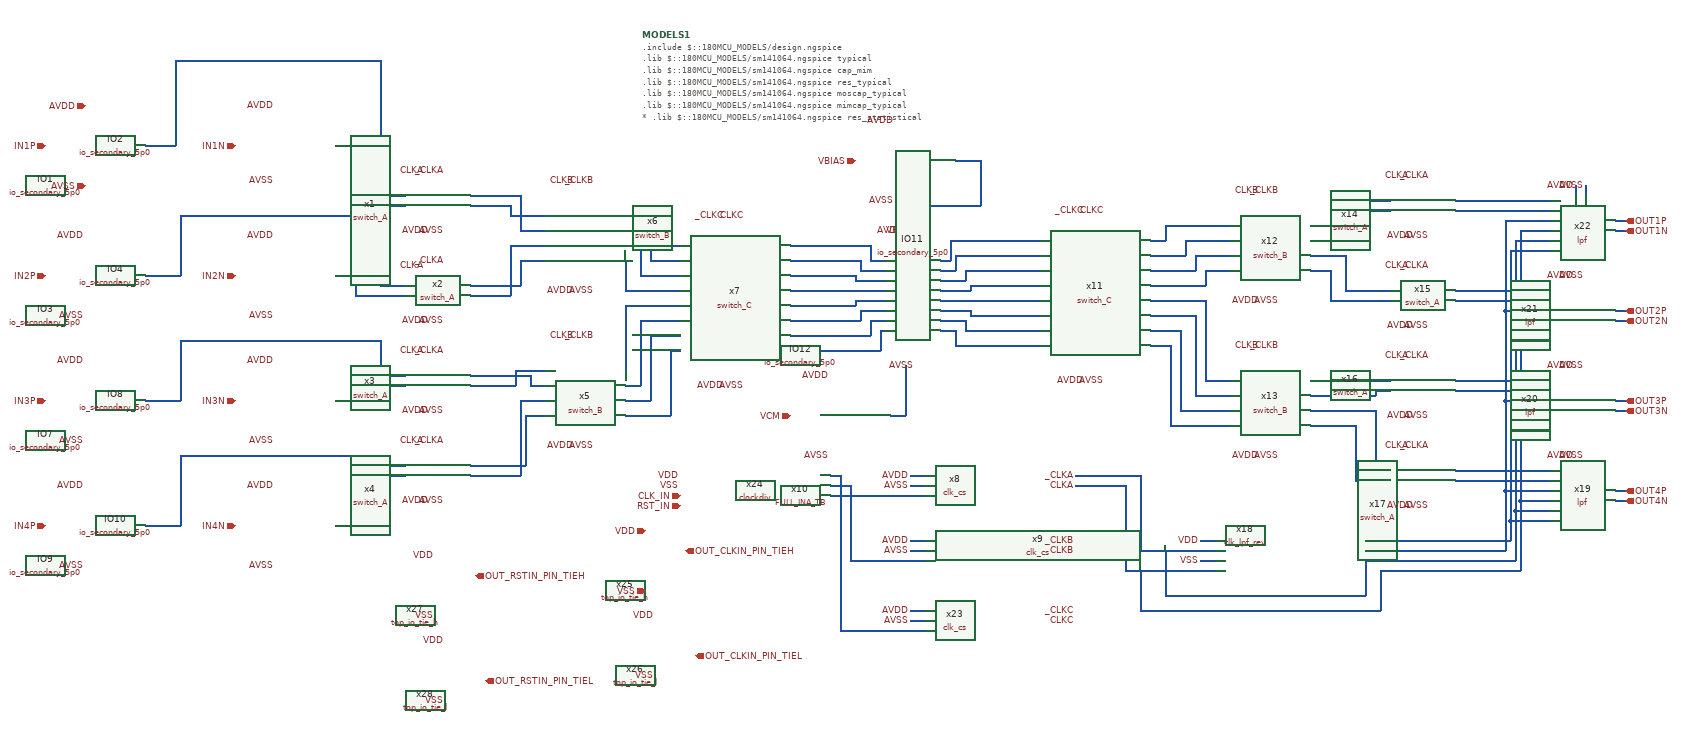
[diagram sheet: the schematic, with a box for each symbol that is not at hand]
v {xschem version=3.4.7 file_version=1.2}
G {}
K {}
V {}
S {}
E {}
N 1560 -610 1590 -610 {lab=AVDD}
N 1560 -590 1590 -590 {lab=AVSS}
N 1560 -570 1590 -570 {lab=#net1}
N 1560 -440 1590 -440 {lab=#net2}
N 1560 -460 1590 -460 {lab=AVSS}
N 1560 -480 1590 -480 {lab=AVDD}
N 1560 -340 1590 -340 {lab=AVDD}
N 1580 -320 1590 -320 {lab=AVSS}
N 1560 -300 1590 -300 {lab=#net3}
N 680 -1170 780 -1170 {lab=#net4}
N 780 -1170 780 -1100 {lab=#net4}
N 780 -1100 830 -1100 {lab=#net4}
N 760 -1130 830 -1130 {lab=#net5}
N 760 -1150 760 -1130 {lab=#net5}
N 680 -1150 760 -1150 {lab=#net5}
N 680 -990 780 -990 {lab=#net6}
N 780 -1040 780 -990 {lab=#net6}
N 780 -1040 830 -1040 {lab=#net6}
N 760 -1070 830 -1070 {lab=#net7}
N 760 -1070 760 -970 {lab=#net7}
N 680 -970 760 -970 {lab=#net7}
N 680 -810 800 -810 {lab=#net8}
N 800 -810 800 -790 {lab=#net8}
N 800 -790 830 -790 {lab=#net8}
N 680 -790 770 -790 {lab=#net9}
N 770 -820 770 -790 {lab=#net9}
N 770 -820 830 -820 {lab=#net9}
N 680 -630 790 -630 {lab=#net10}
N 790 -730 790 -630 {lab=#net10}
N 790 -730 830 -730 {lab=#net10}
N 780 -760 830 -760 {lab=#net11}
N 780 -760 780 -610 {lab=#net11}
N 680 -610 780 -610 {lab=#net11}
N 990 -1130 1060 -1130 {lab=#net12}
N 1060 -1130 1060 -1070 {lab=#net12}
N 1060 -1070 1100 -1070 {lab=#net12}
N 990 -1100 1040 -1100 {lab=#net13}
N 1040 -1100 1040 -1040 {lab=#net13}
N 1040 -1040 1100 -1040 {lab=#net13}
N 990 -1070 1020 -1070 {lab=#net14}
N 1020 -1070 1020 -1010 {lab=#net14}
N 1020 -1010 1100 -1010 {lab=#net14}
N 990 -1040 990 -980 {lab=#net15}
N 990 -980 1100 -980 {lab=#net15}
N 500 -1170 550 -1170 {lab=#net16}
N 500 -990 550 -990 {lab=#net17}
N 500 -810 550 -810 {lab=#net18}
N 500 -630 550 -630 {lab=#net19}
N 2040 -1080 2070 -1080 {lab=#net20}
N 2070 -1110 2070 -1080 {lab=#net20}
N 2070 -1110 2200 -1110 {lab=#net20}
N 2110 -1080 2200 -1080 {lab=#net21}
N 2110 -1080 2110 -1050 {lab=#net21}
N 2040 -1050 2110 -1050 {lab=#net21}
N 2040 -1020 2130 -1020 {lab=#net22}
N 2130 -1050 2130 -1020 {lab=#net22}
N 2130 -1050 2200 -1050 {lab=#net22}
N 2040 -990 2150 -990 {lab=#net23}
N 2150 -1020 2150 -990 {lab=#net23}
N 2150 -1020 2200 -1020 {lab=#net23}
N 2040 -960 2150 -960 {lab=#net24}
N 2150 -960 2150 -800 {lab=#net24}
N 2150 -800 2200 -800 {lab=#net24}
N 2040 -930 2130 -930 {lab=#net25}
N 2130 -930 2130 -770 {lab=#net25}
N 2130 -770 2200 -770 {lab=#net25}
N 2040 -900 2100 -900 {lab=#net26}
N 2100 -900 2100 -740 {lab=#net26}
N 2100 -740 2200 -740 {lab=#net26}
N 2040 -870 2080 -870 {lab=#net27}
N 2080 -870 2080 -710 {lab=#net27}
N 2080 -710 2200 -710 {lab=#net27}
N 2360 -1110 2400 -1110 {lab=#net28}
N 2400 -1160 2400 -1110 {lab=#net28}
N 2400 -1160 2520 -1160 {lab=#net28}
N 2360 -1080 2430 -1080 {lab=#net29}
N 2430 -1140 2430 -1080 {lab=#net29}
N 2430 -1140 2520 -1140 {lab=#net29}
N 2360 -1050 2430 -1050 {lab=#net30}
N 2430 -1050 2430 -980 {lab=#net30}
N 2430 -980 2520 -980 {lab=#net30}
N 2360 -1020 2400 -1020 {lab=#net31}
N 2400 -1020 2400 -960 {lab=#net31}
N 2400 -960 2520 -960 {lab=#net31}
N 2360 -800 2520 -800 {lab=#net32}
N 2360 -770 2490 -770 {lab=#net33}
N 2490 -780 2490 -770 {lab=#net33}
N 2490 -780 2520 -780 {lab=#net33}
N 2360 -740 2490 -740 {lab=#net34}
N 2490 -740 2490 -620 {lab=#net34}
N 2490 -620 2520 -620 {lab=#net34}
N 2360 -710 2450 -710 {lab=#net35}
N 2450 -710 2450 -610 {lab=#net35}
N 2450 -610 2450 -600 {lab=#net35}
N 2450 -600 2520 -600 {lab=#net35}
N 1320 -1070 1360 -1070 {lab=#net36}
N 1320 -1040 1380 -1040 {lab=#net37}
N 1320 -1010 1410 -1010 {lab=#net38}
N 1320 -980 1420 -980 {lab=#net39}
N 1320 -950 1420 -950 {lab=#net40}
N 1320 -920 1400 -920 {lab=#net41}
N 1320 -890 1370 -890 {lab=#net42}
N 1320 -860 1340 -860 {lab=#net43}
N 1790 -1080 1820 -1080 {lab=#net44}
N 1760 -1050 1820 -1050 {lab=#net45}
N 1740 -1020 1820 -1020 {lab=#net46}
N 1710 -990 1820 -990 {lab=#net47}
N 1740 -960 1820 -960 {lab=#net48}
N 1760 -930 1820 -930 {lab=#net49}
N 1780 -900 1820 -900 {lab=#net50}
N 1810 -870 1820 -870 {lab=#net51}
N 1360 -1070 1480 -1070 {lab=#net36}
N 1480 -1070 1480 -1040 {lab=#net36}
N 1480 -1040 1510 -1040 {lab=#net36}
N 1380 -1040 1460 -1040 {lab=#net37}
N 1460 -1040 1460 -1020 {lab=#net37}
N 1460 -1020 1510 -1020 {lab=#net37}
N 1410 -1010 1450 -1010 {lab=#net38}
N 1450 -1010 1450 -1000 {lab=#net38}
N 1450 -1000 1510 -1000 {lab=#net38}
N 1420 -980 1510 -980 {lab=#net39}
N 1420 -950 1450 -950 {lab=#net40}
N 1450 -960 1450 -950 {lab=#net40}
N 1450 -960 1510 -960 {lab=#net40}
N 1400 -920 1460 -920 {lab=#net41}
N 1460 -940 1460 -920 {lab=#net41}
N 1460 -940 1510 -940 {lab=#net41}
N 1370 -890 1480 -890 {lab=#net42}
N 1480 -920 1480 -890 {lab=#net42}
N 1480 -920 1510 -920 {lab=#net42}
N 1340 -860 1500 -860 {lab=#net43}
N 1500 -900 1500 -860 {lab=#net43}
N 1500 -900 1510 -900 {lab=#net43}
N 1620 -900 1650 -900 {lab=#net51}
N 1650 -900 1650 -870 {lab=#net51}
N 1650 -870 1810 -870 {lab=#net51}
N 1670 -900 1780 -900 {lab=#net50}
N 1670 -920 1670 -900 {lab=#net50}
N 1620 -920 1670 -920 {lab=#net50}
N 1680 -930 1760 -930 {lab=#net49}
N 1680 -940 1680 -930 {lab=#net49}
N 1620 -940 1680 -940 {lab=#net49}
N 1620 -960 1740 -960 {lab=#net48}
N 1680 -990 1710 -990 {lab=#net47}
N 1680 -990 1680 -980 {lab=#net47}
N 1620 -980 1680 -980 {lab=#net47}
N 1670 -1020 1740 -1020 {lab=#net46}
N 1670 -1020 1670 -1000 {lab=#net46}
N 1620 -1000 1670 -1000 {lab=#net46}
N 1650 -1050 1760 -1050 {lab=#net45}
N 1650 -1050 1650 -1020 {lab=#net45}
N 1620 -1020 1650 -1020 {lab=#net45}
N 1640 -1080 1790 -1080 {lab=#net44}
N 1640 -1080 1640 -1040 {lab=#net44}
N 1620 -1040 1640 -1040 {lab=#net44}
N 2650 -1140 2820 -1140 {lab=#net52}
N 2140 -480 2170 -480 {lab=VDD}
N 2470 -480 2760 -480 {lab=#net53}
N 2760 -520 2760 -480 {lab=#net53}
N 2760 -520 2820 -520 {lab=#net53}
N 2470 -460 2750 -460 {lab=#net54}
N 2750 -580 2750 -460 {lab=#net54}
N 2750 -580 2820 -580 {lab=#net54}
N 2470 -440 2770 -440 {lab=_CLKA}
N 2770 -540 2770 -440 {lab=_CLKA}
N 2770 -540 2820 -540 {lab=_CLKA}
N 2780 -560 2780 -420 {lab=CLKA}
N 2780 -560 2820 -560 {lab=CLKA}
N 2750 -760 2750 -580 {lab=#net54}
N 2750 -760 2820 -760 {lab=#net54}
N 2750 -940 2750 -760 {lab=#net54}
N 2750 -940 2820 -940 {lab=#net54}
N 2750 -1120 2750 -940 {lab=#net54}
N 2750 -1120 2820 -1120 {lab=#net54}
N 2780 -740 2780 -560 {lab=CLKA}
N 2780 -740 2820 -740 {lab=CLKA}
N 2780 -920 2780 -740 {lab=CLKA}
N 2780 -920 2820 -920 {lab=CLKA}
N 2780 -1100 2780 -920 {lab=CLKA}
N 2780 -1100 2820 -1100 {lab=CLKA}
N 2770 -720 2770 -540 {lab=_CLKA}
N 2770 -720 2820 -720 {lab=_CLKA}
N 2770 -900 2770 -720 {lab=_CLKA}
N 2770 -900 2820 -900 {lab=_CLKA}
N 2770 -1080 2770 -900 {lab=_CLKA}
N 2770 -1080 2820 -1080 {lab=_CLKA}
N 2760 -1060 2820 -1060 {lab=#net53}
N 2760 -1060 2760 -520 {lab=#net53}
N 2760 -700 2820 -700 {lab=#net53}
N 2760 -880 2820 -880 {lab=#net53}
N 2820 -1160 2840 -1160 {lab=#net55}
N 2820 -1140 2840 -1140 {lab=#net52}
N 2820 -1120 2840 -1120 {lab=#net54}
N 2820 -1100 2840 -1100 {lab=CLKA}
N 2820 -1080 2840 -1080 {lab=_CLKA}
N 2820 -1060 2840 -1060 {lab=#net53}
N 2820 -960 2840 -960 {lab=#net56}
N 2820 -940 2840 -940 {lab=#net54}
N 2820 -920 2840 -920 {lab=CLKA}
N 2820 -900 2840 -900 {lab=_CLKA}
N 2820 -880 2840 -880 {lab=#net53}
N 2820 -800 2840 -800 {lab=#net57}
N 2820 -780 2840 -780 {lab=#net58}
N 2820 -760 2840 -760 {lab=#net54}
N 2820 -740 2840 -740 {lab=CLKA}
N 2820 -720 2840 -720 {lab=_CLKA}
N 2820 -700 2840 -700 {lab=#net53}
N 2820 -620 2840 -620 {lab=#net59}
N 2820 -600 2840 -600 {lab=#net60}
N 2820 -580 2840 -580 {lab=#net54}
N 2820 -560 2840 -560 {lab=CLKA}
N 2820 -540 2840 -540 {lab=_CLKA}
N 2820 -520 2840 -520 {lab=#net53}
N 2970 -580 2990 -580 {lab=OUT4P}
N 2970 -560 2990 -560 {lab=OUT4N}
N 2970 -740 2990 -740 {lab=OUT3N}
N 2970 -760 2990 -760 {lab=OUT3P}
N 2970 -920 2990 -920 {lab=OUT2N}
N 2970 -940 2990 -940 {lab=OUT2P}
N 2890 -1190 2890 -1170 {lab=AVDD}
N 2910 -1190 2910 -1170 {lab=AVSS}
N 2970 -1120 2990 -1120 {lab=OUT1P}
N 2970 -1100 2990 -1100 {lab=OUT1N}
N 1560 -320 1580 -320 {lab=AVSS}
N 500 -1150 550 -1150 {lab=#net61}
N 500 -970 550 -970 {lab=#net62}
N 500 -790 550 -790 {lab=#net63}
N 500 -610 550 -610 {lab=#net64}
N 2650 -980 2840 -980 {lab=#net65}
N 2650 -960 2820 -960 {lab=#net56}
N 2650 -800 2820 -800 {lab=#net57}
N 2650 -780 2820 -780 {lab=#net58}
N 2650 -1160 2820 -1160 {lab=#net55}
N 2650 -620 2820 -620 {lab=#net59}
N 2650 -600 2820 -600 {lab=#net60}
N 990 -950 990 -820 {lab=#net66}
N 990 -950 1100 -950 {lab=#net66}
N 990 -790 1020 -790 {lab=#net67}
N 1020 -920 1020 -790 {lab=#net67}
N 1020 -920 1100 -920 {lab=#net67}
N 990 -760 1040 -760 {lab=#net68}
N 1040 -890 1040 -760 {lab=#net68}
N 1040 -890 1100 -890 {lab=#net68}
N 990 -730 1080 -730 {lab=#net69}
N 1080 -860 1080 -730 {lab=#net69}
N 1080 -860 1100 -860 {lab=#net69}
N 2020 -460 2170 -460 {lab=_CLKA}
N 2020 -610 2020 -460 {lab=_CLKA}
N 1890 -610 2020 -610 {lab=_CLKA}
N 1890 -590 1990 -590 {lab=CLKA}
N 1990 -590 1990 -420 {lab=CLKA}
N 1990 -420 2170 -420 {lab=CLKA}
N 2140 -440 2170 -440 {lab=VSS}
N 2500 -420 2780 -420 {lab=CLKA}
N 2070 -460 2070 -370 {lab=_CLKA}
N 2070 -370 2470 -370 {lab=_CLKA}
N 2470 -440 2470 -370 {lab=_CLKA}
N 2020 -420 2020 -340 {lab=CLKA}
N 2020 -340 2500 -340 {lab=CLKA}
N 2500 -420 2500 -340 {lab=CLKA}
N 30 -1270 90 -1270 {lab=#net16}
N 90 -1440 90 -1270 {lab=#net16}
N 90 -1440 500 -1440 {lab=#net16}
N 500 -1440 500 -1170 {lab=#net16}
N 410 -1270 460 -1270 {lab=#net61}
N 460 -1270 460 -1150 {lab=#net61}
N 460 -1150 500 -1150 {lab=#net61}
N 30 -1010 100 -1010 {lab=#net17}
N 100 -1130 100 -1010 {lab=#net17}
N 100 -1130 500 -1130 {lab=#net17}
N 500 -1130 500 -990 {lab=#net17}
N 410 -1010 450 -1010 {lab=#net62}
N 450 -1010 450 -970 {lab=#net62}
N 450 -970 500 -970 {lab=#net62}
N 30 -760 100 -760 {lab=#net18}
N 100 -880 100 -760 {lab=#net18}
N 100 -880 500 -880 {lab=#net18}
N 500 -880 500 -810 {lab=#net18}
N 410 -760 500 -760 {lab=#net63}
N 500 -790 500 -760 {lab=#net63}
N 30 -510 100 -510 {lab=#net19}
N 100 -650 100 -510 {lab=#net19}
N 100 -650 500 -650 {lab=#net19}
N 500 -650 500 -630 {lab=#net19}
N 410 -510 500 -510 {lab=#net64}
N 500 -610 500 -510 {lab=#net64}
N 1400 -610 1420 -610 {lab=#net3}
N 1420 -610 1420 -300 {lab=#net3}
N 1420 -300 1560 -300 {lab=#net3}
N 1400 -590 1440 -590 {lab=#net2}
N 1440 -590 1440 -440 {lab=#net2}
N 1440 -440 1560 -440 {lab=#net2}
N 1400 -570 1560 -570 {lab=#net1}
N 1550 -830 1550 -730 {lab=#net70}
N 1520 -730 1550 -730 {lab=#net70}
N 1650 -1240 1700 -1240 {lab=VBIAS}
N 1570 -1150 1570 -1100 {lab=VBIAS}
N 1570 -1150 1700 -1150 {lab=VBIAS}
N 1700 -1160 1700 -1150 {lab=VBIAS}
N 1700 -1240 1700 -1160 {lab=VBIAS}
C {devices/code_shown.sym} 1024.998521357774 -1491.620232462883 0 0 {name=MODELS1 only_toplevel=true
format="tcleval( @value )"
value="
.include $::180MCU_MODELS/design.ngspice
.lib $::180MCU_MODELS/sm141064.ngspice typical
.lib $::180MCU_MODELS/sm141064.ngspice cap_mim
.lib $::180MCU_MODELS/sm141064.ngspice res_typical
.lib $::180MCU_MODELS/sm141064.ngspice moscap_typical
.lib $::180MCU_MODELS/sm141064.ngspice mimcap_typical
* .lib $::180MCU_MODELS/sm141064.ngspice res_statistical
"}
C {xschem top/Chopper Switch/switch_A.sym} 510 -1100 0 0 {name=x1}
C {xschem top/Chopper Switch/switch_A.sym} 510 -920 0 0 {name=x2}
C {xschem top/Chopper Switch/switch_A.sym} 510 -740 0 0 {name=x3}
C {xschem top/Chopper Switch/switch_A.sym} 510 -560 0 0 {name=x4}
C {xschem top/Chopper Switch/switch_B.sym} 970 -670 0 0 {name=x5}
C {xschem top/Chopper Switch/switch_B.sym} 970 -980 0 0 {name=x6}
C {xschem top/Chopper Switch/switch_C.sym} 1210 -1010 0 0 {name=x7}
C {xschem top/Chopper Switch/switch_C.sym} 1930 -1020 0 0 {name=x11}
C {xschem top/Chopper Switch/switch_B.sym} 2340 -960 0 0 {name=x12}
C {xschem top/Chopper Switch/switch_B.sym} 2340 -650 0 0 {name=x13}
C {xschem top/Chopper Switch/switch_A.sym} 2480 -1090 0 0 {name=x14}
C {xschem top/Chopper Switch/switch_A.sym} 2480 -910 0 0 {name=x15}
C {xschem top/Chopper Switch/switch_A.sym} 2480 -730 0 0 {name=x16}
C {xschem top/LPF/lpf.sym} 2970 -930 0 0 {name=x21}
C {xschem top/LPF/lpf.sym} 2970 -1110 0 0 {name=x22}
C {xschem top/Chopper Switch/switch_A.sym} 2480 -550 0 0 {name=x17}
C {xschem top/INA/FULL_INA_TB.sym} 1320 -510 0 0 {name=x10}
C {lab_wire.sym} 1560 -590 0 0 {name=p86 lab=AVSS}
C {lab_wire.sym} 1560 -610 0 0 {name=p87 lab=AVDD}
C {xschem top/Chopper Switch/Complementary CLK for Switches/clk_cs.sym} 1740 -590 0 0 {name=x8}
C {xschem top/Chopper Switch/Complementary CLK for Switches/clk_cs.sym} 1740 -460 0 0 {name=x9}
C {xschem top/Chopper Switch/Complementary CLK for Switches/clk_cs.sym} 1740 -320 0 0 {name=x23}
C {lab_wire.sym} 1560 -480 0 0 {name=p2 lab=AVDD}
C {lab_wire.sym} 1560 -460 0 0 {name=p3 lab=AVSS}
C {lab_wire.sym} 1560 -340 0 0 {name=p13 lab=AVDD}
C {lab_wire.sym} 1560 -320 0 0 {name=p14 lab=AVSS}
C {lab_wire.sym} 1890 -610 0 0 {name=p88 lab=_CLKA}
C {lab_wire.sym} 1890 -590 0 0 {name=p89 lab=CLKA}
C {lab_wire.sym} 1890 -480 0 0 {name=p94 lab=_CLKB}
C {lab_wire.sym} 1890 -460 0 0 {name=p95 lab=CLKB}
C {lab_wire.sym} 1890 -340 0 0 {name=p96 lab=_CLKC}
C {lab_wire.sym} 1890 -320 0 0 {name=p97 lab=CLKC}
C {lab_wire.sym} 2140 -440 0 0 {name=p50 lab=VSS}
C {lab_wire.sym} 2140 -480 0 0 {name=p98 lab=VDD}
C {lab_wire.sym} 590 -1220 1 0 {name=p12 lab=CLKA}
C {lab_wire.sym} 630 -1220 1 0 {name=p15 lab=_CLKA}
C {lab_wire.sym} 590 -1030 1 0 {name=p16 lab=CLKA}
C {lab_wire.sym} 630 -1040 1 0 {name=p17 lab=_CLKA}
C {lab_wire.sym} 590 -860 1 0 {name=p18 lab=CLKA}
C {lab_wire.sym} 630 -860 1 0 {name=p19 lab=_CLKA}
C {lab_wire.sym} 590 -680 1 0 {name=p20 lab=CLKA}
C {lab_wire.sym} 630 -680 1 0 {name=p21 lab=_CLKA}
C {lab_wire.sym} 630 -560 3 0 {name=p22 lab=AVSS}
C {lab_wire.sym} 600 -560 3 0 {name=p32 lab=AVDD}
C {lab_wire.sym} 630 -740 3 0 {name=p33 lab=AVSS}
C {lab_wire.sym} 600 -740 3 0 {name=p34 lab=AVDD}
C {lab_wire.sym} 630 -920 3 0 {name=p35 lab=AVSS}
C {lab_wire.sym} 600 -920 3 0 {name=p100 lab=AVDD}
C {lab_wire.sym} 630 -1100 3 0 {name=p101 lab=AVSS}
C {lab_wire.sym} 600 -1100 3 0 {name=p102 lab=AVDD}
C {lab_wire.sym} 930 -670 3 0 {name=p23 lab=AVSS}
C {lab_wire.sym} 890 -670 3 0 {name=p24 lab=AVDD}
C {lab_wire.sym} 930 -980 3 0 {name=p25 lab=AVSS}
C {lab_wire.sym} 890 -980 3 0 {name=p26 lab=AVDD}
C {lab_wire.sym} 1230 -790 3 0 {name=p30 lab=AVSS}
C {lab_wire.sym} 1190 -790 3 0 {name=p31 lab=AVDD}
C {lab_wire.sym} 890 -1200 1 0 {name=p29 lab=CLKB}
C {lab_wire.sym} 930 -1200 1 0 {name=p107 lab=_CLKB}
C {lab_wire.sym} 890 -890 1 0 {name=p108 lab=CLKB}
C {lab_wire.sym} 930 -890 1 0 {name=p109 lab=_CLKB}
C {lab_wire.sym} 1190 -1130 1 0 {name=p27 lab=_CLKC}
C {lab_wire.sym} 1230 -1130 1 0 {name=p28 lab=CLKC}
C {lab_wire.sym} 1550 -1100 1 0 {name=p42 lab=AVDD}
C {lab_wire.sym} 1570 -1100 1 0 {name=p43 lab=VBIAS}
C {lab_wire.sym} 1570 -830 3 0 {name=p49 lab=AVSS}
C {opin.sym} 2990 -1120 0 0 {name=p51 lab=OUT1P}
C {opin.sym} 2990 -1100 0 0 {name=p58 lab=OUT1N}
C {opin.sym} 2990 -940 0 0 {name=p59 lab=OUT2P}
C {opin.sym} 2990 -920 0 0 {name=p60 lab=OUT2N}
C {opin.sym} 2990 -760 0 0 {name=p90 lab=OUT3P}
C {opin.sym} 2990 -740 0 0 {name=p91 lab=OUT3N}
C {opin.sym} 2990 -580 0 0 {name=p92 lab=OUT4P}
C {opin.sym} 2990 -560 0 0 {name=p93 lab=OUT4N}
C {lab_wire.sym} 1910 -1140 1 0 {name=p73 lab=_CLKC}
C {lab_wire.sym} 1950 -1140 1 0 {name=p74 lab=CLKC}
C {lab_wire.sym} 1950 -800 3 0 {name=p75 lab=AVSS}
C {lab_wire.sym} 1910 -800 3 0 {name=p139 lab=AVDD}
C {lab_wire.sym} 2260 -1180 1 0 {name=p61 lab=CLKB}
C {lab_wire.sym} 2300 -1180 1 0 {name=p62 lab=_CLKB}
C {lab_wire.sym} 2260 -870 1 0 {name=p63 lab=CLKB}
C {lab_wire.sym} 2300 -870 1 0 {name=p64 lab=_CLKB}
C {lab_wire.sym} 2300 -650 3 0 {name=p65 lab=AVSS}
C {lab_wire.sym} 2260 -650 3 0 {name=p66 lab=AVDD}
C {lab_wire.sym} 2300 -960 3 0 {name=p67 lab=AVSS}
C {lab_wire.sym} 2260 -960 3 0 {name=p68 lab=AVDD}
C {lab_wire.sym} 2560 -1210 1 0 {name=p69 lab=CLKA}
C {lab_wire.sym} 2600 -1210 1 0 {name=p70 lab=_CLKA}
C {lab_wire.sym} 2560 -1030 1 0 {name=p71 lab=CLKA}
C {lab_wire.sym} 2600 -1030 1 0 {name=p72 lab=_CLKA}
C {lab_wire.sym} 2560 -850 1 0 {name=p76 lab=CLKA}
C {lab_wire.sym} 2600 -850 1 0 {name=p77 lab=_CLKA}
C {lab_wire.sym} 2600 -550 3 0 {name=p78 lab=AVSS}
C {lab_wire.sym} 2570 -550 3 0 {name=p79 lab=AVDD}
C {lab_wire.sym} 2600 -730 3 0 {name=p80 lab=AVSS}
C {lab_wire.sym} 2570 -730 3 0 {name=p81 lab=AVDD}
C {lab_wire.sym} 2600 -910 3 0 {name=p140 lab=AVSS}
C {lab_wire.sym} 2570 -910 3 0 {name=p141 lab=AVDD}
C {lab_wire.sym} 2600 -1090 3 0 {name=p142 lab=AVSS}
C {lab_wire.sym} 2570 -1090 3 0 {name=p143 lab=AVDD}
C {xschem top/LPF/lpf.sym} 2970 -750 0 0 {name=x20}
C {xschem top/LPF/lpf.sym} 2970 -570 0 0 {name=x19}
C {lab_wire.sym} 2910 -1190 1 0 {name=p82 lab=AVSS}
C {lab_wire.sym} 2890 -1190 1 0 {name=p83 lab=AVDD}
C {lab_wire.sym} 2890 -1010 1 0 {name=p84 lab=AVDD}
C {lab_wire.sym} 2910 -1010 1 0 {name=p85 lab=AVSS}
C {lab_wire.sym} 2910 -830 1 0 {name=p144 lab=AVSS}
C {lab_wire.sym} 2910 -650 1 0 {name=p145 lab=AVSS}
C {lab_wire.sym} 2890 -830 1 0 {name=p146 lab=AVDD}
C {lab_wire.sym} 2890 -650 1 0 {name=p147 lab=AVDD}
C {xschem top/LPF/Complementary CLK for LPF/clk_lpf_rev.sym} 2320 -450 0 0 {name=x18}
C {gLayout/tutorial/io_secondary_5p0.sym} -170 -1190 0 0 {name=IO1
spiceprefix=X
}
C {gLayout/tutorial/io_secondary_5p0.sym} 210 -1190 0 0 {name=IO2
spiceprefix=X
}
C {gLayout/tutorial/io_secondary_5p0.sym} -170 -930 0 0 {name=IO3
spiceprefix=X
}
C {ipin.sym} -90 -1350 1 0 {name=p41 lab=AVDD}
C {ipin.sym} -90 -1190 3 0 {name=p44 lab=AVSS}
C {lab_wire.sym} 290 -1200 3 0 {name=p45 lab=AVSS}
C {lab_wire.sym} 290 -1350 1 0 {name=p46 lab=AVDD}
C {iopin.sym} -170 -1270 2 0 {name=p47 lab=IN1P}
C {iopin.sym} 210 -1270 2 0 {name=p48 lab=IN1N}
C {lab_wire.sym} -90 -1090 1 0 {name=p52 lab=AVDD}
C {lab_wire.sym} -90 -930 3 0 {name=p53 lab=AVSS}
C {iopin.sym} -170 -1010 2 0 {name=p54 lab=IN2P}
C {gLayout/tutorial/io_secondary_5p0.sym} 210 -930 0 0 {name=IO4
spiceprefix=X
}
C {lab_wire.sym} 290 -1090 1 0 {name=p55 lab=AVDD}
C {lab_wire.sym} 290 -930 3 0 {name=p56 lab=AVSS}
C {iopin.sym} 210 -1010 2 0 {name=p57 lab=IN2N}
C {gLayout/tutorial/io_secondary_5p0.sym} -170 -680 0 0 {name=IO7
spiceprefix=X
}
C {lab_wire.sym} -90 -840 1 0 {name=p115 lab=AVDD}
C {lab_wire.sym} -90 -680 3 0 {name=p116 lab=AVSS}
C {iopin.sym} -170 -760 2 0 {name=p117 lab=IN3P}
C {gLayout/tutorial/io_secondary_5p0.sym} 210 -680 0 0 {name=IO8
spiceprefix=X
}
C {lab_wire.sym} 290 -840 1 0 {name=p120 lab=AVDD}
C {lab_wire.sym} 290 -680 3 0 {name=p121 lab=AVSS}
C {iopin.sym} 210 -760 2 0 {name=p122 lab=IN3N}
C {gLayout/tutorial/io_secondary_5p0.sym} -170 -430 0 0 {name=IO9
spiceprefix=X
}
C {lab_wire.sym} -90 -590 1 0 {name=p124 lab=AVDD}
C {lab_wire.sym} -90 -430 3 0 {name=p125 lab=AVSS}
C {iopin.sym} -170 -510 2 0 {name=p126 lab=IN4P}
C {gLayout/tutorial/io_secondary_5p0.sym} 210 -430 0 0 {name=IO10
spiceprefix=X
}
C {lab_wire.sym} 290 -590 1 0 {name=p128 lab=AVDD}
C {lab_wire.sym} 290 -430 3 0 {name=p129 lab=AVSS}
C {iopin.sym} 210 -510 2 0 {name=p130 lab=IN4N}
C {gLayout/tutorial/io_secondary_5p0.sym} 1450 -1160 0 0 {name=IO11
spiceprefix=X
}
C {gLayout/tutorial/io_secondary_5p0.sym} 1320 -650 0 0 {name=IO12
spiceprefix=X
}
C {lab_wire.sym} 1530 -1320 1 0 {name=p134 lab=AVDD}
C {lab_wire.sym} 1530 -1160 3 0 {name=p135 lab=AVSS}
C {lab_wire.sym} 1400 -650 3 0 {name=p136 lab=AVSS}
C {lab_wire.sym} 1400 -810 1 0 {name=p137 lab=AVDD}
C {iopin.sym} 1320 -730 2 0 {name=p138 lab=VCM}
C {iopin.sym} 1450 -1240 2 0 {name=p148 lab=VBIAS}
C {lab_wire.sym} 2560 -670 1 0 {name=p37 lab=CLKA}
C {lab_wire.sym} 2600 -670 1 0 {name=p38 lab=_CLKA}
C {clockdiv.sym} 1250 -580 0 0 {name=x24}
C {lab_wire.sym} 1100 -610 0 0 {name=p1 lab=VDD}
C {lab_wire.sym} 1100 -590 0 0 {name=p4 lab=VSS}
C {ipin.sym} 1100 -570 0 0 {name=p36 lab=CLK_IN}
C {ipin.sym} 1100 -550 0 0 {name=p39 lab=RST_IN}
C {LVS digital block/Luighi Punya Untuk Referensi/top_io_tie_h.sym} 990 -380 0 0 {name=x25}
C {LVS digital block/Luighi Punya Untuk Referensi/top_io_tie_l.sym} 1010 -210 0 0 {name=x26}
C {lab_wire.sym} 1050 -330 0 0 {name=p40 lab=VDD}
C {ipin.sym} 1030 -500 0 0 {name=p103 lab=VDD}
C {lab_wire.sym} 1050 -210 0 0 {name=p104 lab=VSS}
C {ipin.sym} 1030 -380 0 0 {name=p105 lab=VSS}
C {opin.sym} 1130 -250 0 0 {name=p106 lab=OUT_CLKIN_PIN_TIEL}
C {opin.sym} 1110 -460 0 0 {name=p110 lab=OUT_CLKIN_PIN_TIEH}
C {LVS digital block/Luighi Punya Untuk Referensi/top_io_tie_h.sym} 570 -330 0 0 {name=x27}
C {LVS digital block/Luighi Punya Untuk Referensi/top_io_tie_l.sym} 590 -160 0 0 {name=x28}
C {lab_wire.sym} 630 -280 0 0 {name=p111 lab=VDD}
C {lab_wire.sym} 610 -450 0 0 {name=p112 lab=VDD}
C {lab_wire.sym} 630 -160 0 0 {name=p113 lab=VSS}
C {lab_wire.sym} 610 -330 0 0 {name=p114 lab=VSS}
C {opin.sym} 710 -200 0 0 {name=p119 lab=OUT_RSTIN_PIN_TIEL}
C {opin.sym} 690 -410 0 0 {name=p123 lab=OUT_RSTIN_PIN_TIEH}
